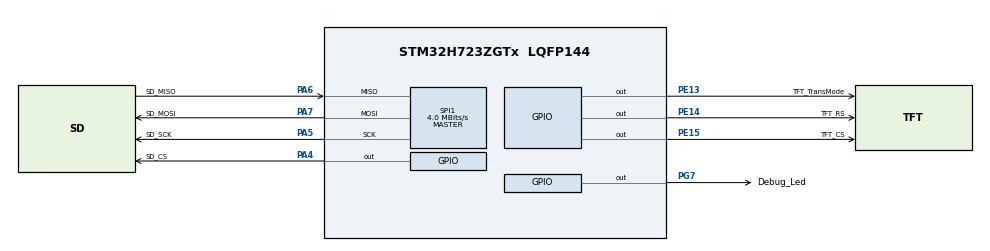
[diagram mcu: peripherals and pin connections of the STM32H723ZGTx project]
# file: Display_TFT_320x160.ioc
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CORTEX_M7.default_mode_Activation=1
Dma.Request0=SPI1_RX
Dma.Request1=SPI1_TX
Dma.SPI1_RX.0.Direction=DMA_PERIPH_TO_MEMORY
Dma.SPI1_RX.0.EventEnable=DISABLE
Dma.SPI1_RX.0.FIFOMode=DMA_FIFOMODE_DISABLE
Dma.SPI1_RX.0.Instance=DMA1_Stream0
Dma.SPI1_RX.0.MemDataAlignment=DMA_MDATAALIGN_BYTE
Dma.SPI1_RX.0.MemInc=DMA_MINC_ENABLE
Dma.SPI1_RX.0.Mode=DMA_NORMAL
Dma.SPI1_RX.0.PeriphDataAlignment=DMA_PDATAALIGN_BYTE
Dma.SPI1_RX.0.PeriphInc=DMA_PINC_DISABLE
Dma.SPI1_RX.0.Polarity=HAL_DMAMUX_REQ_GEN_RISING
Dma.SPI1_RX.0.Priority=DMA_PRIORITY_LOW
Dma.SPI1_RX.0.RequestNumber=1
Dma.SPI1_RX.0.SignalID=NONE
Dma.SPI1_RX.0.SyncEnable=DISABLE
Dma.SPI1_RX.0.SyncPolarity=HAL_DMAMUX_SYNC_NO_EVENT
Dma.SPI1_RX.0.SyncRequestNumber=1
Dma.SPI1_RX.0.SyncSignalID=NONE
Dma.SPI1_TX.1.Direction=DMA_MEMORY_TO_PERIPH
Dma.SPI1_TX.1.EventEnable=DISABLE
Dma.SPI1_TX.1.FIFOMode=DMA_FIFOMODE_DISABLE
Dma.SPI1_TX.1.Instance=DMA1_Stream1
Dma.SPI1_TX.1.MemDataAlignment=DMA_MDATAALIGN_BYTE
Dma.SPI1_TX.1.MemInc=DMA_MINC_ENABLE
Dma.SPI1_TX.1.Mode=DMA_NORMAL
Dma.SPI1_TX.1.PeriphDataAlignment=DMA_PDATAALIGN_BYTE
Dma.SPI1_TX.1.PeriphInc=DMA_PINC_DISABLE
Dma.SPI1_TX.1.Polarity=HAL_DMAMUX_REQ_GEN_RISING
Dma.SPI1_TX.1.Priority=DMA_PRIORITY_LOW
Dma.SPI1_TX.1.RequestNumber=1
Dma.SPI1_TX.1.SignalID=NONE
Dma.SPI1_TX.1.SyncEnable=DISABLE
Dma.SPI1_TX.1.SyncPolarity=HAL_DMAMUX_SYNC_NO_EVENT
Dma.SPI1_TX.1.SyncRequestNumber=1
Dma.SPI1_TX.1.SyncSignalID=NONE
FATFS._MAX_SS=4096
FATFS._USE_LABEL=1
FATFS._USE_LFN=3
Mcu.Family=STM32H7
Mcu.Name=STM32H723ZGTx
Mcu.Package=LQFP144
NVIC.DMA1_Stream0_IRQn=true\:0\:0\:false\:false\:true\:false\:true\:true
NVIC.DMA1_Stream1_IRQn=true\:0\:0\:false\:false\:true\:false\:true\:true
NVIC.PriorityGroup=NVIC_PRIORITYGROUP_4
NVIC.SPI1_IRQn=true\:0\:0\:false\:false\:true\:false\:true\:true
PA13(JTMS/SWDIO).Mode=Serial_Wire
PA13(JTMS/SWDIO).Signal=DEBUG_JTMS-SWDIO
PA14(JTCK/SWCLK).Mode=Serial_Wire
PA14(JTCK/SWCLK).Signal=DEBUG_JTCK-SWCLK
PA4.GPIO_Label=SD_CS
PA4.PinState=GPIO_PIN_SET
PA4.Signal=GPIO_Output
PA5.GPIO_Label=SD_SCK
PA5.Mode=Full_Duplex_Master
PA5.Signal=SPI1_SCK
PA6.GPIO_Label=SD_MISO
PA6.Mode=Full_Duplex_Master
PA6.Signal=SPI1_MISO
PA7.GPIO_Label=SD_MOSI
PA7.Mode=Full_Duplex_Master
PA7.Signal=SPI1_MOSI
PE13.GPIO_Label=TFT_TransMode
PE13.Signal=GPIO_Output
PE14.GPIO_Label=TFT_RS
PE14.Signal=GPIO_Output
PE15.GPIO_Label=TFT_CS
PE15.Signal=GPIO_Output
PG7.GPIO_Label=Debug_Led
PG7.Signal=GPIO_Output
PH0-OSC_IN.Mode=HSE-External-Oscillator
PH0-OSC_IN.Signal=RCC_OSC_IN
PH1-OSC_OUT.Mode=HSE-External-Oscillator
PH1-OSC_OUT.Signal=RCC_OSC_OUT
ProjectManager.HeapSize=0x200
ProjectManager.StackSize=0x400
ProjectManager.TargetToolchain=CMake
RCC.ADCFreq_Value=129000000
RCC.APB1Freq_Value=64000000
RCC.APB2Freq_Value=32000000
RCC.APB3Freq_Value=64000000
RCC.APB4Freq_Value=64000000
RCC.CortexFreq_Value=64000000
RCC.D2PPRE2=RCC_APB2_DIV2
RCC.DIVM1=4
RCC.DIVN1=12
RCC.DIVQ1=3
RCC.HCLKFreq_Value=64000000
RCC.PLLFRACN=0
RCC.SYSCLKFreq_VALUE=64000000
RCC.USBFreq_Value=64000000
SPI1.BaudRatePrescaler=SPI_BAUDRATEPRESCALER_16
SPI1.CalculateBaudRate=4.0 MBits/s
SPI1.DataSize=SPI_DATASIZE_8BIT
SPI1.Direction=SPI_DIRECTION_2LINES
SPI1.Mode=SPI_MODE_MASTER
SPI1.NSSPMode=SPI_NSS_PULSE_DISABLE
SPI1.VirtualType=VM_MASTER
VP_FATFS_VS_Generic.Mode=User_defined
VP_MEMORYMAP_VS_MEMORYMAP.Mode=CurAppReg
board=custom

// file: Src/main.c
/* USER CODE BEGIN Header */
/**
  ******************************************************************************
  * @file           : main.c
  * @brief          : Main program body
  ******************************************************************************
  * @attention
  *
  * Copyright (c) 2025 STMicroelectronics.
  * All rights reserved.
  *
  * This software is licensed under terms that can be found in the LICENSE file
  * in the root directory of this software component.
  * If no LICENSE file comes with this software, it is provided AS-IS.
  *
  ******************************************************************************
  */
/* USER CODE END Header */
#include "main.h"
#include "fatfs.h"

/* USER CODE BEGIN Includes */
#include "sd_functions.h"
/* USER CODE END Includes */

SPI_HandleTypeDef hspi1;
DMA_HandleTypeDef hdma_spi1_rx;
DMA_HandleTypeDef hdma_spi1_tx;

void SystemClock_Config(void);
static void MPU_Config(void);
static void MX_GPIO_Init(void);
static void MX_DMA_Init(void);
static void MX_SPI1_Init(void);

int main(void)
{

  /* MPU Configuration--------------------------------------------------------*/
  MPU_Config();

  /* MCU Configuration--------------------------------------------------------*/

  /* Reset of all peripherals, Initializes the Flash interface and the Systick. */
  HAL_Init();

  /* Configure the system clock */
  SystemClock_Config();

  /* Initialize all configured peripherals */
  MX_GPIO_Init();
  MX_DMA_Init();
  MX_SPI1_Init();
  /* USER CODE BEGIN 2 */
  while (1)
  {
    if (sd_mount() == FR_OK)
    {
      break;
    }
    HAL_Delay(100);
  }
  UINT br;
uint8_t bufr[100];
sd_read_file("note.txt", bufr, 20, &br,0);
  /* USER CODE END 2 */

  /* Infinite loop */
  /* USER CODE BEGIN WHILE */
  while (1)
  {
	  HAL_GPIO_TogglePin(Debug_Led_GPIO_Port, Debug_Led_Pin);
	  HAL_Delay(1000);
    /* USER CODE END WHILE */

  }
}

void SystemClock_Config(void)
{
  RCC_OscInitTypeDef RCC_OscInitStruct = {0};
  RCC_ClkInitTypeDef RCC_ClkInitStruct = {0};

  /** Supply configuration update enable
  */
  HAL_PWREx_ConfigSupply(PWR_LDO_SUPPLY);

  /** Configure the main internal regulator output voltage
  */
  __HAL_PWR_VOLTAGESCALING_CONFIG(PWR_REGULATOR_VOLTAGE_SCALE3);

  while(!__HAL_PWR_GET_FLAG(PWR_FLAG_VOSRDY)) {}

  /** Initializes the RCC Oscillators according to the specified parameters
  * in the RCC_OscInitTypeDef structure.
  */
  RCC_OscInitStruct.OscillatorType = RCC_OSCILLATORTYPE_HSI;
  RCC_OscInitStruct.HSIState = RCC_HSI_DIV1;
  RCC_OscInitStruct.HSICalibrationValue = 64;
  RCC_OscInitStruct.PLL.PLLState = RCC_PLL_ON;
  RCC_OscInitStruct.PLL.PLLSource = RCC_PLLSOURCE_HSI;
  RCC_OscInitStruct.PLL.PLLM = 4;
  RCC_OscInitStruct.PLL.PLLN = 12;
  RCC_OscInitStruct.PLL.PLLP = 2;
  RCC_OscInitStruct.PLL.PLLQ = 3;
  RCC_OscInitStruct.PLL.PLLR = 2;
  RCC_OscInitStruct.PLL.PLLRGE = RCC_PLL1VCIRANGE_3;
  RCC_OscInitStruct.PLL.PLLVCOSEL = RCC_PLL1VCOWIDE;
  RCC_OscInitStruct.PLL.PLLFRACN = 0;
  if (HAL_RCC_OscConfig(&RCC_OscInitStruct) != HAL_OK)
  {
    Error_Handler();
  }

  /** Initializes the CPU, AHB and APB buses clocks
  */
  RCC_ClkInitStruct.ClockType = RCC_CLOCKTYPE_HCLK|RCC_CLOCKTYPE_SYSCLK
                              |RCC_CLOCKTYPE_PCLK1|RCC_CLOCKTYPE_PCLK2
                              |RCC_CLOCKTYPE_D3PCLK1|RCC_CLOCKTYPE_D1PCLK1;
  RCC_ClkInitStruct.SYSCLKSource = RCC_SYSCLKSOURCE_HSI;
  RCC_ClkInitStruct.SYSCLKDivider = RCC_SYSCLK_DIV1;
  RCC_ClkInitStruct.AHBCLKDivider = RCC_HCLK_DIV1;
  RCC_ClkInitStruct.APB3CLKDivider = RCC_APB3_DIV1;
  RCC_ClkInitStruct.APB1CLKDivider = RCC_APB1_DIV1;
  RCC_ClkInitStruct.APB2CLKDivider = RCC_APB2_DIV1;
  RCC_ClkInitStruct.APB4CLKDivider = RCC_APB4_DIV1;

  if (HAL_RCC_ClockConfig(&RCC_ClkInitStruct, FLASH_LATENCY_1) != HAL_OK)
  {
    Error_Handler();
  }
}

static void MX_SPI1_Init(void)
{

  /* SPI1 parameter configuration*/
  hspi1.Instance = SPI1;
  hspi1.Init.Mode = SPI_MODE_MASTER;
  hspi1.Init.Direction = SPI_DIRECTION_2LINES;
  hspi1.Init.DataSize = SPI_DATASIZE_8BIT;
  hspi1.Init.CLKPolarity = SPI_POLARITY_LOW;
  hspi1.Init.CLKPhase = SPI_PHASE_1EDGE;
  hspi1.Init.NSS = SPI_NSS_SOFT;
  hspi1.Init.BaudRatePrescaler = SPI_BAUDRATEPRESCALER_32;
  hspi1.Init.FirstBit = SPI_FIRSTBIT_MSB;
  hspi1.Init.TIMode = SPI_TIMODE_DISABLE;
  hspi1.Init.CRCCalculation = SPI_CRCCALCULATION_DISABLE;
  hspi1.Init.CRCPolynomial = 0x0;
  hspi1.Init.NSSPMode = SPI_NSS_PULSE_DISABLE;
  hspi1.Init.NSSPolarity = SPI_NSS_POLARITY_LOW;
  hspi1.Init.FifoThreshold = SPI_FIFO_THRESHOLD_01DATA;
  hspi1.Init.TxCRCInitializationPattern = SPI_CRC_INITIALIZATION_ALL_ZERO_PATTERN;
  hspi1.Init.RxCRCInitializationPattern = SPI_CRC_INITIALIZATION_ALL_ZERO_PATTERN;
  hspi1.Init.MasterSSIdleness = SPI_MASTER_SS_IDLENESS_00CYCLE;
  hspi1.Init.MasterInterDataIdleness = SPI_MASTER_INTERDATA_IDLENESS_00CYCLE;
  hspi1.Init.MasterReceiverAutoSusp = SPI_MASTER_RX_AUTOSUSP_DISABLE;
  hspi1.Init.MasterKeepIOState = SPI_MASTER_KEEP_IO_STATE_DISABLE;
  hspi1.Init.IOSwap = SPI_IO_SWAP_DISABLE;
  if (HAL_SPI_Init(&hspi1) != HAL_OK)
  {
    Error_Handler();
  }

}

static void MX_DMA_Init(void)
{

  /* DMA controller clock enable */
  __HAL_RCC_DMA1_CLK_ENABLE();

  /* DMA interrupt init */
  /* DMA1_Stream0_IRQn interrupt configuration */
  HAL_NVIC_SetPriority(DMA1_Stream0_IRQn, 0, 0);
  HAL_NVIC_EnableIRQ(DMA1_Stream0_IRQn);
  /* DMA1_Stream1_IRQn interrupt configuration */
  HAL_NVIC_SetPriority(DMA1_Stream1_IRQn, 0, 0);
  HAL_NVIC_EnableIRQ(DMA1_Stream1_IRQn);

}

static void MX_GPIO_Init(void)
{
  GPIO_InitTypeDef GPIO_InitStruct = {0};

  /* GPIO Ports Clock Enable */
  __HAL_RCC_GPIOA_CLK_ENABLE();
  __HAL_RCC_GPIOG_CLK_ENABLE();

  /*Configure GPIO pin Output Level */
  HAL_GPIO_WritePin(SD_CS_GPIO_Port, SD_CS_Pin, GPIO_PIN_SET);

  /*Configure GPIO pin Output Level */
  HAL_GPIO_WritePin(Debug_Led_GPIO_Port, Debug_Led_Pin, GPIO_PIN_RESET);

  /*Configure GPIO pin : SD_CS_Pin */
  GPIO_InitStruct.Pin = SD_CS_Pin;
  GPIO_InitStruct.Mode = GPIO_MODE_OUTPUT_PP;
  GPIO_InitStruct.Pull = GPIO_NOPULL;
  GPIO_InitStruct.Speed = GPIO_SPEED_FREQ_LOW;
  HAL_GPIO_Init(SD_CS_GPIO_Port, &GPIO_InitStruct);

  /*Configure GPIO pin : Debug_Led_Pin */
  GPIO_InitStruct.Pin = Debug_Led_Pin;
  GPIO_InitStruct.Mode = GPIO_MODE_OUTPUT_PP;
  GPIO_InitStruct.Pull = GPIO_NOPULL;
  GPIO_InitStruct.Speed = GPIO_SPEED_FREQ_LOW;
  HAL_GPIO_Init(Debug_Led_GPIO_Port, &GPIO_InitStruct);

}

 /* MPU Configuration */

void MPU_Config(void)
{
  MPU_Region_InitTypeDef MPU_InitStruct = {0};

  /* Disables the MPU */
  HAL_MPU_Disable();

  /** Initializes and configures the Region and the memory to be protected
  */
  MPU_InitStruct.Enable = MPU_REGION_ENABLE;
  MPU_InitStruct.Number = MPU_REGION_NUMBER0;
  MPU_InitStruct.BaseAddress = 0x0;
  MPU_InitStruct.Size = MPU_REGION_SIZE_4GB;
  MPU_InitStruct.SubRegionDisable = 0x87;
  MPU_InitStruct.TypeExtField = MPU_TEX_LEVEL0;
  MPU_InitStruct.AccessPermission = MPU_REGION_NO_ACCESS;
  MPU_InitStruct.DisableExec = MPU_INSTRUCTION_ACCESS_DISABLE;
  MPU_InitStruct.IsShareable = MPU_ACCESS_SHAREABLE;
  MPU_InitStruct.IsCacheable = MPU_ACCESS_NOT_CACHEABLE;
  MPU_InitStruct.IsBufferable = MPU_ACCESS_NOT_BUFFERABLE;

  HAL_MPU_ConfigRegion(&MPU_InitStruct);
  /* Enables the MPU */
  HAL_MPU_Enable(MPU_PRIVILEGED_DEFAULT);

}

void Error_Handler(void)
{
  __disable_irq();
  while (1)
  {
  }
}
